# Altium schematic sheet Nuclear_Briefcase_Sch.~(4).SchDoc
size A; SheetNumber: 1; SheetTotal: 1

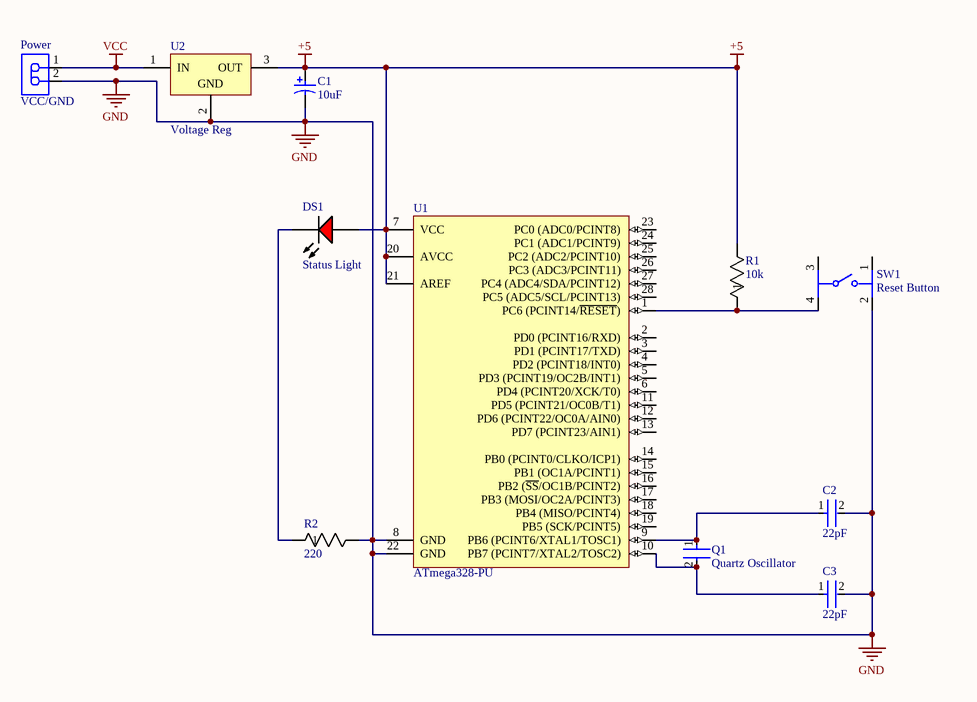
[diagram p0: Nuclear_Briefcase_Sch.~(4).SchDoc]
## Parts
C1  10uF  [CAPPR55-200-1100X500X1200]
C2  22pF  [FP-RCE0DB-MFG]
C3  22pF  [FP-RCE0DB-MFG]
DS1  Status Light  [LED-2P-2.28-3MM_A]
Power  VCC/GND  [TECO-640456-2_V]
Q1  Quartz Oscillator  [FP-RCE0DB-MFG]
R1  10k  [RES_AC07_VIS]
R2  220  [RES_AC05_VIS]
SW1  Reset Button  [FP-PTS645SM43SMTR92LFS-MFG]
U1  ATmega328-PU  [28P3]
U2  Voltage Reg  [TO220]

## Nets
+5: C1.1 DS1.1(A) R1.2 U1.7(VCC) U1.20(AVCC) U1.21(AREF) U2.3(OUT)
GND: C1.2 C2.2 C3.2 Power.2 R2.2 SW1.2 U1.8(GND) U1.22(GND) U2.2(GND)
VCC: Power.1 U2.1(IN)
NetC2_1: C2.1 Q1.1 U1.9(PB6_(PCINT6/XTAL1/TOSC1))
NetC3_1: C3.1 Q1.2 U1.10(PB7_(PCINT7/XTAL2/TOSC2))
NetDS1_2: DS1.2(K) R2.1
NetR1_1: R1.1 SW1.4 U1.1(PC6_(PCINT14/~{RESET}))

Not connected (* = marked no-connect by the designer): SW1 1 3; U1 2(PD0_(PCINT16/RXD)) 3(PD1_(PCINT17/TXD)) 4(PD2_(PCINT18/INT0)) 5(PD3_(PCINT19/OC2B/INT1)) 6(PD4_(PCINT20/XCK/T0)) 11(PD5_(PCINT21/OC0B/T1)) 12(PD6_(PCINT22/OC0A/AIN0)) 13(PD7_(PCINT23/AIN1)) 14(PB0_(PCINT0/CLKO/ICP1)) 15(PB1_(OC1A/PCINT1)) 16(PB2_(~{SS}/OC1B/PCINT2)) 17(PB3_(MOSI/OC2A/PCINT3)) 18(PB4_(MISO/PCINT4)) 19(PB5_(SCK/PCINT5)) 23(PC0_(ADC0/PCINT8)) 24(PC1_(ADC1/PCINT9)) 25(PC2_(ADC2/PCINT10)) 26(PC3_(ADC3/PCINT11)) 27(PC4_(ADC4/SDA/PCINT12)) 28(PC5_(ADC5/SCL/PCINT13))

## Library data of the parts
C1 = CMP-1665-00038-2: Aluminum Electrolytic Capacitor, 10 uF, +/- 20%, 50 V, -40 to 85 degC, 2-Pin THD, RoHS, Bulk; Manufacturer: Panasonic; Life (Hours): 2000Hour; Lead/Base Style: Straight; Dissipation Factor: 0.12%; Leakage Current: 3uA; Dielectric Material: Aluminium; Lead Diameter: 0.5mm; Voltage Rating: 50V; Ripple Current: 65mA
C2 C3 Q1 = CMP-06035-047347-1: Cap Ceramic 22pF 100V C0G ±5% Radial 2.5mm +125°C Ammo Pack; Lead Diameter: 0.5mm; Lead/Base Style: Straight
DS1 = CMP-007-00007-2: Red LED, 80 mW, 30 mA, -25 to 85 degC, 2-Pin THD; Manufacturer: Shenzhen CGX
Power = CMP-2000-05417-1: Male Header, Pitch 2.54 mm, 1 x 2 Position, Height 10.49 mm, Tail Length 3.556 mm, -55 to 105 degC, RoHS, Bulk; Manufacturer: TE Connectivity; Standards: RoHSCompliant,ELVCompliant,UL94V-0; Material, Housing: Polyester; Agency Approvals: CSA,UL; Brand/Series: MTA-100Series; Contact Centerline Spacing: 0.100 / in.; Material, Contact: CopperAlloy; Current, Rating: 5 / A; Color, Housing: White; Contact Termination Area Plating: Tin; Special Features: Pinstrip; Number of Positions: 2; Pin Spacing: 0.1 / "; Temperature, Operating: -55to+105 / degC; Angle: Straight; Mount Angle: Vertical; Connector Type: MTA-100; Primary Type: InterconnectSystem; Voltage, Rating: 250 / V; Mounting Hole Size: 0.04 / "
R1 = CMP-00030-42824152-1: AC07000001002JAC00 Resistor, 10 kOhm, ± 5%, 7 W, Axial Leaded, Wirewound, General Purpose; Voltage Rating (DC): 265V; Power Rating: 7W; Temperature Coefficient: 180ppm/°C; Resistance: 10kΩ
R2 = CMP-00030-39746845-1: AC05000002200JAC00 Resistor, 220 Ohm, ± 5%, 5 W, Axial Leaded, Wirewound, General Purpose; Lead Diameter: 800µm; Resistance: 220Ω; Voltage Rating: 33V; Temperature Coefficient: -10ppm/°C; Power Rating: 5W
SW1 = CMP-2000-05160-2: SWITCH TACTILE SPST-NO 0.05A 12V; Contact Resistance: 100mR; Throw Configuration: SPST; Illumination Type: Non-Illuminated; Mechanical Life: 100000Cycles; Current Rating: 50mA; Switch Function: Off-Mom; Actuator Length: 0.85mm; Actuator Material: Nylon; Actuator Type: Standard; Operating Force: 160gf
U1 = CMP-0095-00015-2: 8-bit AVR Microcontroller, 32KB Flash, 1KB EEPROM, 2KB SRAM, 28-pin PDIP, Industrial Grade (-40°C to 85°C)
U2 = CMP-019-00018-3: Positive Voltage Regulator IC, 1.5 A, 5 V, 0 to 125 degC, 3-Pin TO-220, RoHS, Tube; Manufacturer: STMicroelectronics; Max Input Voltage: 35V; Min Supply Voltage: 8V; Nominal Output Voltage: 5V; Outputs: 1; Output Current: 1.5A; Dropout Voltage: 2V; Max Supply Voltage: 20V; Min Input Voltage: 7V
